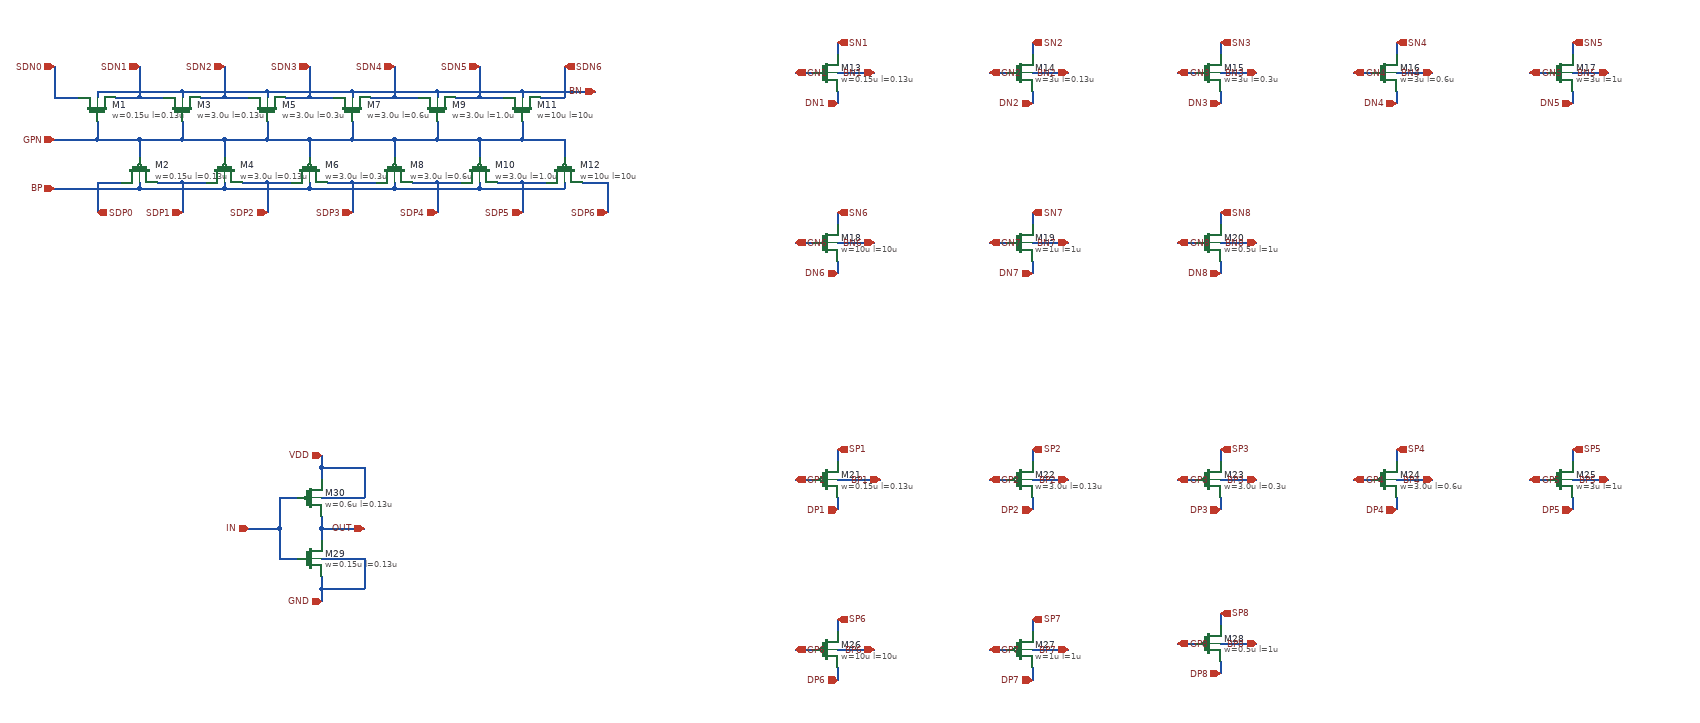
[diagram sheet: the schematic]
v {xschem version=3.4.5 file_version=1.2
}
G {}
K {}
V {}
S {}
E {}
N 1360 -500 1420 -500 {
lab=BN1}
N 1360 -550 1360 -530 {
lab=SN1}
N 1360 -470 1360 -450 {
lab=DN1}
N 1290 -500 1320 -500 {
lab=GN1}
N 1680 -500 1740 -500 {
lab=BN2}
N 1680 -550 1680 -530 {
lab=SN2}
N 1680 -470 1680 -450 {
lab=DN2}
N 1610 -500 1640 -500 {
lab=GN2}
N 1990 -500 2050 -500 {
lab=BN3}
N 1990 -550 1990 -530 {
lab=SN3}
N 1990 -470 1990 -450 {
lab=DN3}
N 1920 -500 1950 -500 {
lab=GN3}
N 2280 -500 2340 -500 {
lab=BN4}
N 2280 -550 2280 -530 {
lab=SN4}
N 2280 -470 2280 -450 {
lab=DN4}
N 2210 -500 2240 -500 {
lab=GN4}
N 2570 -500 2630 -500 {
lab=BN5}
N 2570 -550 2570 -530 {
lab=SN5}
N 2570 -470 2570 -450 {
lab=DN5}
N 2500 -500 2530 -500 {
lab=GN5}
N 1360 -220 1420 -220 {
lab=BN6}
N 1360 -270 1360 -250 {
lab=SN6}
N 1360 -190 1360 -170 {
lab=DN6}
N 1290 -220 1320 -220 {
lab=GN6}
N 1680 -220 1740 -220 {
lab=BN7}
N 1680 -270 1680 -250 {
lab=SN7}
N 1680 -190 1680 -170 {
lab=DN7}
N 1610 -220 1640 -220 {
lab=GN7}
N 1990 -220 2050 -220 {
lab=BN}
N 1990 -270 1990 -250 {
lab=SN8}
N 1990 -190 1990 -170 {
lab=DN8}
N 1920 -220 1950 -220 {
lab=GN8}
N 510 250 510 270 {
lab=OUT}
N 510 250 580 250 {
lab=OUT}
N 510 230 510 250 {
lab=OUT}
N 440 200 470 200 {
lab=IN}
N 440 250 440 300 {
lab=IN}
N 440 300 470 300 {
lab=IN}
N 390 250 440 250 {
lab=IN}
N 440 200 440 250 {
lab=IN}
N 510 300 580 300 {
lab=GND}
N 510 200 580 200 {
lab=VDD}
N 510 150 510 170 {
lab=VDD}
N 510 350 510 370 {
lab=GND}
N 580 150 580 200 {
lab=VDD}
N 510 150 580 150 {
lab=VDD}
N 510 130 510 150 {
lab=VDD}
N 580 300 580 350 {
lab=GND}
N 510 350 580 350 {
lab=GND}
N 510 330 510 350 {
lab=GND}
N 1360 120 1360 140 {
lab=SP1}
N 1360 200 1360 220 {
lab=DP1}
N 1290 170 1320 170 {
lab=GP1}
N 1680 170 1740 170 {
lab=BP2}
N 1680 120 1680 140 {
lab=SP2}
N 1680 200 1680 220 {
lab=DP2}
N 1610 170 1640 170 {
lab=GP2}
N 1990 170 2050 170 {
lab=BP3}
N 1990 120 1990 140 {
lab=SP3}
N 1990 200 1990 220 {
lab=DP3}
N 1920 170 1950 170 {
lab=GP3}
N 2280 170 2340 170 {
lab=BP4}
N 2280 120 2280 140 {
lab=SP4}
N 2280 200 2280 220 {
lab=DP4}
N 2210 170 2240 170 {
lab=GP4}
N 2570 170 2630 170 {
lab=BP5}
N 2570 120 2570 140 {
lab=SP5}
N 2570 200 2570 220 {
lab=DP5}
N 2500 170 2530 170 {
lab=GP5}
N 1360 450 1420 450 {
lab=BP6}
N 1360 400 1360 420 {
lab=SP6}
N 1360 480 1360 500 {
lab=DP6}
N 1290 450 1320 450 {
lab=GP6}
N 1680 450 1740 450 {
lab=BP7}
N 1680 400 1680 420 {
lab=SP7}
N 1680 480 1680 500 {
lab=DP7}
N 1610 450 1640 450 {
lab=GP7}
N 1990 440 2050 440 {
lab=BP8}
N 1990 390 1990 410 {
lab=SP8}
N 1990 470 1990 490 {
lab=DP8}
N 1920 440 1950 440 {
lab=GP8}
N 1360 170 1430 170 {
lab=BP1}
N 910 -390 910 -360 {
lab=GPN}
N 840 -420 840 -390 {
lab=GPN}
N 770 -390 770 -360 {
lab=GPN}
N 630 -390 700 -390 {
lab=GPN}
N 700 -420 700 -390 {
lab=GPN}
N 840 -390 910 -390 {
lab=GPN}
N 770 -390 840 -390 {
lab=GPN}
N 700 -390 770 -390 {
lab=GPN}
N 630 -390 630 -360 {
lab=GPN}
N 560 -390 630 -390 {
lab=GPN}
N 560 -420 560 -390 {
lab=GPN}
N 490 -390 560 -390 {
lab=GPN}
N 490 -390 490 -360 {
lab=GPN}
N 420 -390 490 -390 {
lab=GPN}
N 420 -420 420 -390 {
lab=GPN}
N 350 -390 420 -390 {
lab=GPN}
N 350 -390 350 -360 {
lab=GPN}
N 280 -390 350 -390 {
lab=GPN}
N 280 -420 280 -390 {
lab=GPN}
N 210 -390 280 -390 {
lab=GPN}
N 210 -390 210 -360 {
lab=GPN}
N 140 -390 210 -390 {
lab=GPN}
N 140 -420 140 -390 {
lab=GPN}
N 70 -390 140 -390 {
lab=GPN}
N 280 -320 320 -320 {
lab=SDP1}
N 420 -320 460 -320 {
lab=SDP2}
N 560 -320 600 -320 {
lab=SDP3}
N 700 -320 740 -320 {
lab=SDP4}
N 840 -320 880 -320 {
lab=SDP5}
N 770 -460 810 -460 {
lab=SDN5}
N 630 -460 670 -460 {
lab=SDN4}
N 490 -460 530 -460 {
lab=SDN3}
N 350 -460 390 -460 {
lab=SDN2}
N 210 -460 250 -460 {
lab=SDN1}
N 70 -460 110 -460 {
lab=SDN0}
N 940 -320 980 -320 {
lab=SDP6}
N 280 -320 280 -270 {
lab=SDP1}
N 240 -320 280 -320 {
lab=SDP1}
N 420 -320 420 -270 {
lab=SDP2}
N 380 -320 420 -320 {
lab=SDP2}
N 560 -320 560 -270 {
lab=SDP3}
N 520 -320 560 -320 {
lab=SDP3}
N 700 -320 700 -270 {
lab=SDP4}
N 660 -320 700 -320 {
lab=SDP4}
N 840 -320 840 -270 {
lab=SDP5}
N 800 -320 840 -320 {
lab=SDP5}
N 770 -510 770 -460 {
lab=SDN5}
N 730 -460 770 -460 {
lab=SDN5}
N 630 -510 630 -460 {
lab=SDN4}
N 590 -460 630 -460 {
lab=SDN4}
N 490 -510 490 -460 {
lab=SDN3}
N 450 -460 490 -460 {
lab=SDN3}
N 350 -510 350 -460 {
lab=SDN2}
N 310 -460 350 -460 {
lab=SDN2}
N 210 -510 210 -460 {
lab=SDN1}
N 170 -460 210 -460 {
lab=SDN1}
N 70 -510 70 -460 {
lab=SDN0}
N 980 -320 980 -270 {
lab=SDP6}
N 140 -320 180 -320 {
lab=SDP0}
N 140 -320 140 -270 {
lab=SDP0}
N 870 -460 910 -460 {
lab=SDN6}
N 910 -510 910 -460 {
lab=SDN6}
N 70 -310 210 -310 {
lab=BP}
N 770 -310 910 -310 {
lab=BP}
N 630 -310 770 -310 {
lab=BP}
N 490 -310 630 -310 {
lab=BP}
N 350 -310 490 -310 {
lab=BP}
N 210 -310 350 -310 {
lab=BP}
N 140 -470 140 -460 {
lab=BN}
N 840 -470 960 -470 {
lab=BN}
N 280 -470 280 -460 {
lab=BN}
N 140 -470 280 -470 {
lab=BN}
N 420 -470 420 -460 {
lab=BN}
N 280 -470 420 -470 {
lab=BN}
N 560 -470 560 -460 {
lab=BN}
N 420 -470 560 -470 {
lab=BN}
N 700 -470 700 -460 {
lab=BN}
N 560 -470 700 -470 {
lab=BN}
N 840 -470 840 -460 {
lab=BN}
N 700 -470 840 -470 {
lab=BN}
N 210 -320 210 -310 {
lab=BP}
N 770 -320 770 -310 {
lab=BP}
N 910 -320 910 -310 {
lab=BP}
N 630 -320 630 -310 {
lab=BP}
N 490 -320 490 -310 {
lab=BP}
N 350 -320 350 -310 {
lab=BP}
C {sg13g2_pr/sg13_lv_nmos.sym} 1340 -500 0 0 {name=M13
l=0.13u
w=0.15u
ng=1
m=1
model=sg13_lv_nmos
spiceprefix=X
}
C {iopin.sym} 1420 -500 0 0 {name=p18 lab=BN1}
C {iopin.sym} 1360 -550 1 1 {name=p19 lab=SN1}
C {iopin.sym} 1360 -450 1 0 {name=p20 lab=DN1}
C {iopin.sym} 1290 -500 0 1 {name=p21 lab=GN1}
C {sg13g2_pr/sg13_lv_nmos.sym} 1660 -500 0 0 {name=M14
l=0.13u
w=3u
ng=1
m=1
model=sg13_lv_nmos
spiceprefix=X
}
C {iopin.sym} 1740 -500 0 0 {name=p22 lab=BN2}
C {iopin.sym} 1680 -550 1 1 {name=p23 lab=SN2}
C {iopin.sym} 1680 -450 1 0 {name=p24 lab=DN2}
C {iopin.sym} 1610 -500 0 1 {name=p25 lab=GN2}
C {sg13g2_pr/sg13_lv_nmos.sym} 1970 -500 0 0 {name=M15
l=0.3u
w=3u
ng=1
m=1
model=sg13_lv_nmos
spiceprefix=X
}
C {iopin.sym} 2050 -500 0 0 {name=p26 lab=BN3}
C {iopin.sym} 1990 -550 1 1 {name=p27 lab=SN3}
C {iopin.sym} 1990 -450 1 0 {name=p28 lab=DN3}
C {iopin.sym} 1920 -500 0 1 {name=p29 lab=GN3}
C {sg13g2_pr/sg13_lv_nmos.sym} 2260 -500 0 0 {name=M16
l=0.6u
w=3u
ng=1
m=1
model=sg13_lv_nmos
spiceprefix=X
}
C {iopin.sym} 2340 -500 0 0 {name=p30 lab=BN4}
C {iopin.sym} 2280 -550 1 1 {name=p31 lab=SN4}
C {iopin.sym} 2280 -450 1 0 {name=p32 lab=DN4}
C {iopin.sym} 2210 -500 0 1 {name=p33 lab=GN4}
C {sg13g2_pr/sg13_lv_nmos.sym} 2550 -500 0 0 {name=M17
l=1u
w=3u
ng=1
m=1
model=sg13_lv_nmos
spiceprefix=X
}
C {iopin.sym} 2630 -500 0 0 {name=p34 lab=BN5}
C {iopin.sym} 2570 -550 1 1 {name=p35 lab=SN5}
C {iopin.sym} 2570 -450 1 0 {name=p36 lab=DN5}
C {iopin.sym} 2500 -500 0 1 {name=p37 lab=GN5}
C {sg13g2_pr/sg13_lv_nmos.sym} 1340 -220 0 0 {name=M18
l=10u
w=10u
ng=1
m=1
model=sg13_lv_nmos
spiceprefix=X
}
C {iopin.sym} 1420 -220 0 0 {name=p38 lab=BN6}
C {iopin.sym} 1360 -270 1 1 {name=p39 lab=SN6}
C {iopin.sym} 1360 -170 1 0 {name=p40 lab=DN6}
C {iopin.sym} 1290 -220 0 1 {name=p41 lab=GN6}
C {sg13g2_pr/sg13_lv_nmos.sym} 1660 -220 0 0 {name=M19
l=1u
w=1u
ng=1
m=1
model=sg13_lv_nmos
spiceprefix=X
}
C {iopin.sym} 1740 -220 0 0 {name=p42 lab=BN7}
C {iopin.sym} 1680 -270 1 1 {name=p43 lab=SN7}
C {iopin.sym} 1680 -170 1 0 {name=p44 lab=DN7}
C {iopin.sym} 1610 -220 0 1 {name=p45 lab=GN7}
C {sg13g2_pr/sg13_lv_nmos.sym} 1970 -220 0 0 {name=M20
l=1u
w=0.5u
ng=1
m=1
model=sg13_lv_nmos
spiceprefix=X
}
C {iopin.sym} 2050 -220 0 0 {name=p46 lab=BN8}
C {iopin.sym} 1990 -270 1 1 {name=p47 lab=SN8}
C {iopin.sym} 1990 -170 1 0 {name=p48 lab=DN8}
C {iopin.sym} 1920 -220 0 1 {name=p49 lab=GN8}
C {sg13g2_pr/sg13_lv_pmos.sym} 1340 170 0 0 {name=M21
l=0.13u
w=0.15u
ng=1
m=1
model=sg13_lv_pmos
spiceprefix=X
}
C {sg13g2_pr/sg13_lv_pmos.sym} 1660 170 0 0 {name=M22
l=0.13u
w=3.0u
ng=1
m=1
model=sg13_lv_pmos
spiceprefix=X
}
C {sg13g2_pr/sg13_lv_pmos.sym} 1970 170 0 0 {name=M23
l=0.3u
w=3.0u
ng=1
m=1
model=sg13_lv_pmos
spiceprefix=X
}
C {sg13g2_pr/sg13_lv_pmos.sym} 2260 170 0 0 {name=M24
l=0.6u
w=3.0u
ng=1
m=1
model=sg13_lv_pmos
spiceprefix=X
}
C {sg13g2_pr/sg13_lv_pmos.sym} 2550 170 0 0 {name=M25
l=1u
w=3u
ng=1
m=1
model=sg13_lv_pmos
spiceprefix=X
}
C {sg13g2_pr/sg13_lv_pmos.sym} 1340 450 0 0 {name=M26
l=10u
w=10u
ng=1
m=1
model=sg13_lv_pmos
spiceprefix=X
}
C {sg13g2_pr/sg13_lv_pmos.sym} 1660 450 0 0 {name=M27
l=1u
w=1u
ng=1
m=1
model=sg13_lv_pmos
spiceprefix=X
}
C {sg13g2_pr/sg13_lv_pmos.sym} 1970 440 0 0 {name=M28
l=1u
w=0.5u
ng=1
m=1
model=sg13_lv_pmos
spiceprefix=X
}
C {sg13g2_pr/sg13_lv_nmos.sym} 490 300 0 0 {name=M29
l=0.13u
w=0.15u
ng=1
m=1
model=sg13_lv_nmos
spiceprefix=X
}
C {sg13g2_pr/sg13_lv_pmos.sym} 490 200 0 0 {name=M30
l=0.13u
w=0.6u
ng=1
m=1
model=sg13_lv_pmos
spiceprefix=X
}
C {iopin.sym} 580 250 0 0 {name=p82 lab=OUT}
C {iopin.sym} 390 250 2 0 {name=p83 lab=IN}
C {iopin.sym} 510 130 3 0 {name=p84 lab=VDD}
C {iopin.sym} 510 370 1 0 {name=p85 lab=GND}
C {iopin.sym} 1430 170 0 0 {name=p86 lab=BP1}
C {iopin.sym} 1360 120 1 1 {name=p87 lab=SP1}
C {iopin.sym} 1360 220 1 0 {name=p88 lab=DP1}
C {iopin.sym} 1290 170 0 1 {name=p89 lab=GP1}
C {iopin.sym} 1740 170 0 0 {name=p90 lab=BP2}
C {iopin.sym} 1680 120 1 1 {name=p91 lab=SP2}
C {iopin.sym} 1680 220 1 0 {name=p92 lab=DP2}
C {iopin.sym} 1610 170 0 1 {name=p93 lab=GP2}
C {iopin.sym} 2050 170 0 0 {name=p94 lab=BP3}
C {iopin.sym} 1990 120 1 1 {name=p95 lab=SP3}
C {iopin.sym} 1990 220 1 0 {name=p96 lab=DP3}
C {iopin.sym} 1920 170 0 1 {name=p97 lab=GP3}
C {iopin.sym} 2340 170 0 0 {name=p98 lab=BP4}
C {iopin.sym} 2280 120 1 1 {name=p99 lab=SP4}
C {iopin.sym} 2280 220 1 0 {name=p100 lab=DP4}
C {iopin.sym} 2210 170 0 1 {name=p101 lab=GP4}
C {iopin.sym} 2630 170 0 0 {name=p102 lab=BP5}
C {iopin.sym} 2570 120 1 1 {name=p103 lab=SP5}
C {iopin.sym} 2570 220 1 0 {name=p104 lab=DP5}
C {iopin.sym} 2500 170 0 1 {name=p105 lab=GP5}
C {iopin.sym} 1420 450 0 0 {name=p106 lab=BP6}
C {iopin.sym} 1360 400 1 1 {name=p107 lab=SP6}
C {iopin.sym} 1360 500 1 0 {name=p108 lab=DP6}
C {iopin.sym} 1290 450 0 1 {name=p109 lab=GP6}
C {iopin.sym} 1740 450 0 0 {name=p110 lab=BP7}
C {iopin.sym} 1680 400 1 1 {name=p111 lab=SP7}
C {iopin.sym} 1680 500 1 0 {name=p112 lab=DP7}
C {iopin.sym} 1610 450 0 1 {name=p113 lab=GP7}
C {iopin.sym} 2050 440 0 0 {name=p114 lab=BP8}
C {iopin.sym} 1990 390 1 1 {name=p115 lab=SP8}
C {iopin.sym} 1990 490 1 0 {name=p116 lab=DP8}
C {iopin.sym} 1920 440 0 1 {name=p117 lab=GP8}
C {sg13g2_pr/sg13_lv_nmos.sym} 140 -440 1 1 {name=M1
l=0.13u
w=0.15u
ng=1
m=1
model=sg13_lv_nmos
spiceprefix=X
}
C {sg13g2_pr/sg13_lv_pmos.sym} 210 -340 3 1 {name=M2
l=0.13u
w=0.15u
ng=1
m=1
model=sg13_lv_pmos
spiceprefix=X
}
C {sg13g2_pr/sg13_lv_nmos.sym} 280 -440 1 1 {name=M3
l=0.13u
w=3.0u
ng=1
m=1
model=sg13_lv_nmos
spiceprefix=X
}
C {sg13g2_pr/sg13_lv_pmos.sym} 350 -340 3 1 {name=M4
l=0.13u
w=3.0u
ng=1
m=1
model=sg13_lv_pmos
spiceprefix=X
}
C {sg13g2_pr/sg13_lv_nmos.sym} 420 -440 1 1 {name=M5
l=0.3u
w=3.0u
ng=1
m=1
model=sg13_lv_nmos
spiceprefix=X
}
C {sg13g2_pr/sg13_lv_pmos.sym} 490 -340 3 1 {name=M6
l=0.3u
w=3.0u
ng=1
m=1
model=sg13_lv_pmos
spiceprefix=X
}
C {sg13g2_pr/sg13_lv_nmos.sym} 560 -440 1 1 {name=M7
l=0.6u
w=3.0u
ng=1
m=1
model=sg13_lv_nmos
spiceprefix=X
}
C {sg13g2_pr/sg13_lv_pmos.sym} 630 -340 3 1 {name=M8
l=0.6u
w=3.0u
ng=1
m=1
model=sg13_lv_pmos
spiceprefix=X
}
C {sg13g2_pr/sg13_lv_nmos.sym} 700 -440 1 1 {name=M9
l=1.0u
w=3.0u
ng=1
m=1
model=sg13_lv_nmos
spiceprefix=X
}
C {sg13g2_pr/sg13_lv_pmos.sym} 770 -340 3 1 {name=M10
l=1.0u
w=3.0u
ng=1
m=1
model=sg13_lv_pmos
spiceprefix=X
}
C {sg13g2_pr/sg13_lv_nmos.sym} 840 -440 1 1 {name=M11
l=10u
w=10u
ng=1
m=1
model=sg13_lv_nmos
spiceprefix=X
}
C {sg13g2_pr/sg13_lv_pmos.sym} 910 -340 3 1 {name=M12
l=10u
w=10u
ng=1
m=1
model=sg13_lv_pmos
spiceprefix=X
}
C {iopin.sym} 70 -390 2 0 {name=p4 lab=GPN}
C {iopin.sym} 280 -270 1 0 {name=p6 lab=SDP1}
C {iopin.sym} 420 -270 1 0 {name=p7 lab=SDP2}
C {iopin.sym} 560 -270 1 0 {name=p8 lab=SDP3}
C {iopin.sym} 700 -270 1 0 {name=p9 lab=SDP4}
C {iopin.sym} 840 -270 1 0 {name=p10 lab=SDP5}
C {iopin.sym} 770 -510 3 0 {name=p11 lab=SDN5}
C {iopin.sym} 630 -510 3 0 {name=p12 lab=SDN4}
C {iopin.sym} 490 -510 3 0 {name=p13 lab=SDN3}
C {iopin.sym} 350 -510 3 0 {name=p14 lab=SDN2}
C {iopin.sym} 210 -510 3 0 {name=p15 lab=SDN1}
C {iopin.sym} 70 -510 3 0 {name=p3 lab=SDN0}
C {iopin.sym} 980 -270 1 0 {name=p2 lab=SDP6}
C {iopin.sym} 140 -270 3 1 {name=p1 lab=SDP0}
C {iopin.sym} 910 -510 1 1 {name=p5 lab=SDN6}
C {iopin.sym} 70 -310 2 0 {name=p16 lab=BP}
C {iopin.sym} 960 -470 0 0 {name=p17 lab=BN}
